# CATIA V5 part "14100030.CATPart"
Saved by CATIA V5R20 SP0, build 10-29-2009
Part number: 14100030
Definition: NONE
Nomenclature: 14100030
Source: Unknown
Description: 14100030
Bounding box of the stored display mesh (mm): x -15 to 60, y -64 to 53.915, z -54.1 to 54.1
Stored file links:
  C:\Users\Utente\Desktop\IO LAVORO\3D X SITO CF\X SITO\PLASTICA\RF2\14100030.CATPart

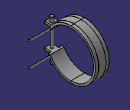
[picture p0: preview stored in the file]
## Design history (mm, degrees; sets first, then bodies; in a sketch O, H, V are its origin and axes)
Body1 "14100030" (main body)
  Solid1: solid without history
